VERSION 5.8 ;
BUSBITCHARS "[]" ;
DIVIDERCHAR "/" ;

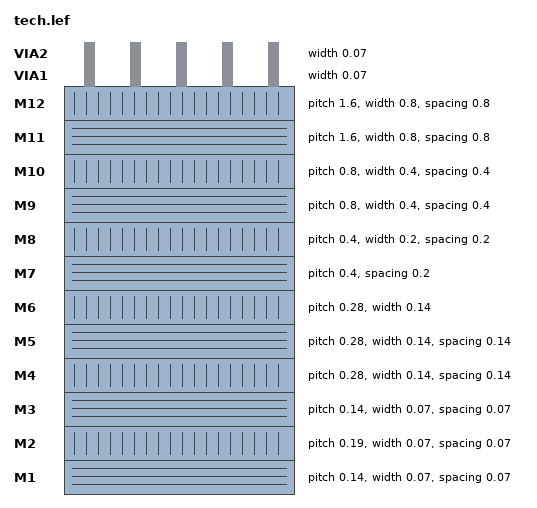
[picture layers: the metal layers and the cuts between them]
LAYER M1
  TYPE ROUTING ;
  DIRECTION HORIZONTAL ;
  PITCH 0.14 ;
  WIDTH 0.07 ;
  SPACING 0.07 ;
END M1

LAYER M2
  TYPE ROUTING ;
  DIRECTION VERTICAL ;
  PITCH 0.19 ;
  WIDTH 0.07 ;
  SPACING 0.07 ;
  SPACING 0.07 LENGTHTHRESHOLD 1.0 ;
  SPACING 0.30 RANGE 0.3 10.0 ;
  SPACING 0.90 RANGE 10.05 100000.0 ;
END M2

LAYER M3
  TYPE ROUTING ;
  DIRECTION HORIZONTAL ;
  PITCH 0.14 ;
  WIDTH 0.07 ;
  SPACING 0.07 ;
END M3

LAYER M4
  TYPE ROUTING ;
  DIRECTION VERTICAL ;
  PITCH 0.28 ;
  WIDTH 0.14 ;
  SPACING 0.14 ;
END M4

LAYER M5
  TYPE ROUTING ;
  DIRECTION HORIZONTAL ;
  PITCH 0.28 ;
  WIDTH 0.14 ;
  SPACING 0.14 ;
END M5

LAYER M6
  TYPE ROUTING ;
  DIRECTION VERTICAL ;
  PITCH 0.28 ;
  WIDTH 0.14 ;
  SPACINGTABLE
    PARALLELRUNLENGTH 0.0000 0.3000 0.9000
      WIDTH 0.0000 0.1400 0.1400 0.1400
      WIDTH 0.0900 0.1400 0.2000 0.2000
      WIDTH 1.5000 0.2000 0.5000 0.9000 ;
END M6

LAYER M7
  TYPE ROUTING ;
  DIRECTION HORIZONTAL ;
  PITCH 0.40 ;
  MINWIDTH 0.20 ;
  SPACING 0.20 ;
END M7

LAYER M8
  TYPE ROUTING ;
  DIRECTION VERTICAL;
  PITCH 0.40 ;
  WIDTH 0.20 ;
  SPACING 0.20 ;
END M8

LAYER M9
  TYPE ROUTING ;
  DIRECTION HORIZONTAL ;
  PITCH 0.80 ;
  WIDTH 0.40 ;
  SPACING 0.40 ;
END M9

LAYER M10
  TYPE ROUTING ;
  DIRECTION VERTICAL ;
  PITCH 0.80 ;
  WIDTH 0.40 ;
  SPACING 0.40 ;
END M10

LAYER M11
  TYPE ROUTING ;
  DIRECTION HORIZONTAL ;
  PITCH 1.60 ;
  WIDTH 0.80 ;
  SPACING 0.80 ;
END M11

LAYER M12
  TYPE ROUTING ;
  DIRECTION VERTICAL ;
  PITCH 1.60 ;
  WIDTH 0.80 ;
  SPACING 0.80 ;
END M12

LAYER VIA1
  TYPE CUT ;
  WIDTH 0.07 ;
END VIA1

LAYER VIA2
  TYPE CUT ;
  WIDTH 0.07 ;
END VIA2

LAYER OVERLAP
  TYPE OVERLAP ;
END OVERLAP
